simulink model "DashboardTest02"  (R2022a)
settings: Solver=VariableStepAuto  StartTime=0.0  StopTime=20  MaxStep=1e-3  RelTol=1e-3
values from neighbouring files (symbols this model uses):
  w = [2 1.5 1]    [Grh_deco.m]    (also in prop_deco.m = -2:2:2; rocket.m = gradient(z); squarWave.m = sum(y); solvSOR.m = varargin{1,2})
  z = vz*t - 1/2*g*t.^2    [rocket.m]

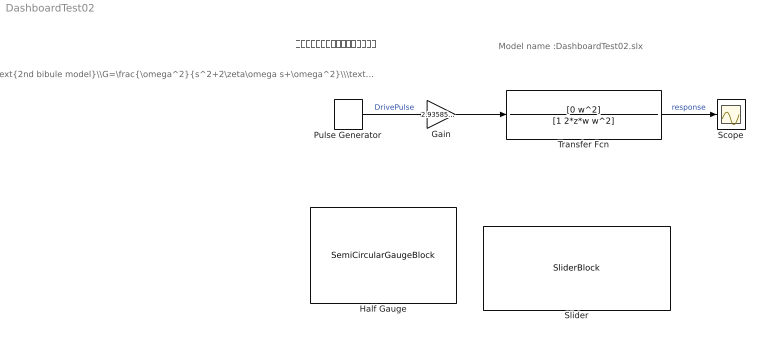
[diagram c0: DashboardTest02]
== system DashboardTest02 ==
  note: Model name :DashboardTest02.slx
  note: $\text{2nd bibule model}\\G=\frac{\omega^2}{s^2+2\zeta\omega s+\omega^2}\\\text{Parametors:}\\\zeta=0.9,\omega=1\\\text{System Parameter}\,\text{Gain}\,K\,\text{(Defualt Value}\,3\text{)}\\\text{(Adjusted by Slide Gain)}$
  note: 振動系伝達関数のシミュレーション
  Gain : Gain  Gain=2.935855263157895
  Half Gauge : SemiCircularGaugeBlock  ScaleMax=1
  Pulse Generator : DiscretePulseGenerator  PulseType=Time based  Period=10  PulseWidth=5
  Scope : Scope
  Slider : SliderBlock  ScaleMax=10
  Transfer Fcn : TransferFcn  Numerator=[0 w^2]  Denominator=[1 2*z*w w^2]
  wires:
  Pulse Generator/1 -> Gain/1  "DrivePulse"
  Transfer Fcn/1 -> Scope/1  "response"
  Gain/1 -> Transfer Fcn/1
